One B-rep face of a CAD part: STEP entity #833.
In plain terms, the planar face has unit normal (1, 0, 0).
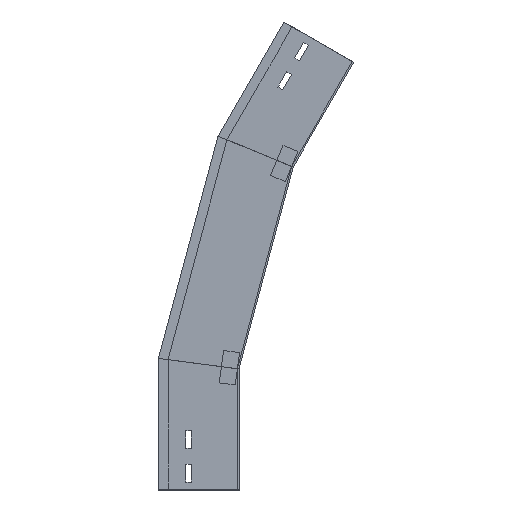
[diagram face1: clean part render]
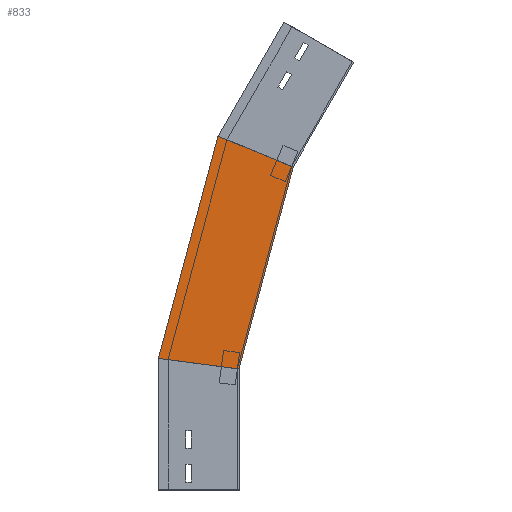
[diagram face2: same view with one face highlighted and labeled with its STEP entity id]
Its self-contained STEP definition (entity closure, numbers rounded to 3 decimals):
#1 = CARTESIAN_POINT ( 'NONE',  ( 0., 3.774, 135.915 ) ) ;
#8 = AXIS2_PLACEMENT_3D ( 'NONE', #1, #485, #939 ) ;
#48 = CARTESIAN_POINT ( 'NONE',  ( 0., 26.151, 438.773 ) ) ;
#74 = ORIENTED_EDGE ( 'NONE', *, *, #1362, .F. ) ;
#129 = DIRECTION ( 'NONE',  ( 0., -0.991, -0.131 ) ) ;
#133 = CARTESIAN_POINT ( 'NONE',  ( 0., 3.774, 135.915 ) ) ;
#139 = CARTESIAN_POINT ( 'NONE',  ( 0., -100.025, 386.509 ) ) ;
#194 = CARTESIAN_POINT ( 'NONE',  ( 0., 100.367, 161.797 ) ) ;
#224 = EDGE_LOOP ( 'NONE', ( #1462, #477, #74, #651 ) ) ;
#303 = VERTEX_POINT ( 'NONE', #48 ) ;
#367 = EDGE_CURVE ( 'NONE', #1255, #303, #541, .T. ) ;
#467 = PLANE ( 'NONE',  #8 ) ;
#477 = ORIENTED_EDGE ( 'NONE', *, *, #618, .T. ) ;
#485 = DIRECTION ( 'NONE',  ( 1., 0., 0. ) ) ;
#508 = CARTESIAN_POINT ( 'NONE',  ( 0., 0., 150. ) ) ;
#541 = LINE ( 'NONE', #194, #746 ) ;
#615 = EDGE_CURVE ( 'NONE', #1255, #1366, #975, .T. ) ;
#618 = EDGE_CURVE ( 'NONE', #303, #774, #1079, .T. ) ;
#651 = ORIENTED_EDGE ( 'NONE', *, *, #615, .F. ) ;
#746 = VECTOR ( 'NONE', #885, 1000. ) ;
#768 = CARTESIAN_POINT ( 'NONE',  ( 0., 100., 163.165 ) ) ;
#774 = VERTEX_POINT ( 'NONE', #1492 ) ;
#833 = ADVANCED_FACE ( 'NONE', ( #1081 ), #467, .T. ) ;
#845 = VECTOR ( 'NONE', #857, 1000. ) ;
#857 = DIRECTION ( 'NONE',  ( 0., -0.924, -0.383 ) ) ;
#860 = DIRECTION ( 'NONE',  ( 0., -0.259, 0.966 ) ) ;
#885 = DIRECTION ( 'NONE',  ( 0., -0.259, 0.966 ) ) ;
#939 = DIRECTION ( 'NONE',  ( 0., 0., -1. ) ) ;
#975 = LINE ( 'NONE', #1408, #1493 ) ;
#1076 = VECTOR ( 'NONE', #860, 1000. ) ;
#1079 = LINE ( 'NONE', #139, #845 ) ;
#1081 = FACE_OUTER_BOUND ( 'NONE', #224, .T. ) ;
#1255 = VERTEX_POINT ( 'NONE', #768 ) ;
#1318 = LINE ( 'NONE', #133, #1076 ) ;
#1362 = EDGE_CURVE ( 'NONE', #1366, #774, #1318, .T. ) ;
#1366 = VERTEX_POINT ( 'NONE', #508 ) ;
#1408 = CARTESIAN_POINT ( 'NONE',  ( 0., -19.411, 147.444 ) ) ;
#1462 = ORIENTED_EDGE ( 'NONE', *, *, #367, .T. ) ;
#1492 = CARTESIAN_POINT ( 'NONE',  ( 0., -67.034, 400.175 ) ) ;
#1493 = VECTOR ( 'NONE', #129, 1000. ) ;
